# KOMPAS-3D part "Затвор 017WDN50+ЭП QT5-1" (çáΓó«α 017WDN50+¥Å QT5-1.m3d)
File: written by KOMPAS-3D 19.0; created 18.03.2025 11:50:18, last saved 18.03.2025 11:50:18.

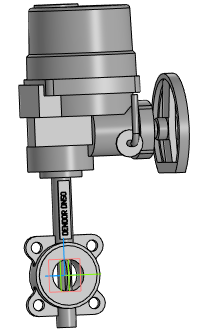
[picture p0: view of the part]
Document properties: Полное имя файла: Затвор 017WDN50+ЭП QT5-1.a3d

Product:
- Part/product: Затвор 017WDN50+ЭП QT5-1
    Масса: 43.3714

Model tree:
1. Операция без истории:1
